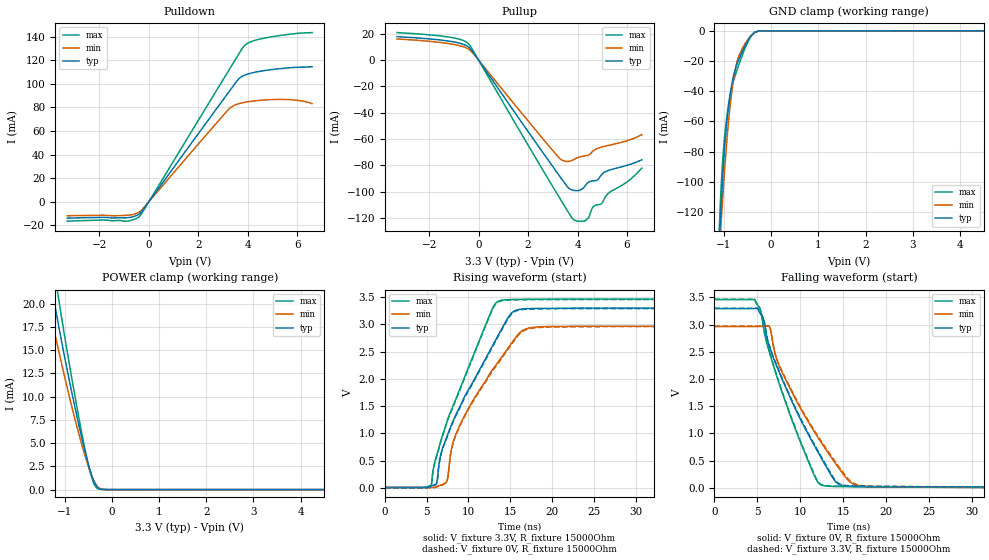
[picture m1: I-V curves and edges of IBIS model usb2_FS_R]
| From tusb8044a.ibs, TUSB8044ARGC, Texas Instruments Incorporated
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|   USB 2.0 Fast Speed mode, for DP pin 6MHz
[Model]   usb2_FS_R
Model_type   I/O
Polarity   Non-Inverting
Enable   Active-High
Vmeas = 1.54
Vref = 0
Rref = 15000
Cref = 50pF
Vinl = 0.8V
Vinh = 2.0V
|   typ   min   max
|   (nom PVT)   (Fast PVT)   (slow PVT)
C_comp   9.0376pF   8.9385pF   9.1512pF
[Voltage Range]   3.3   2.97   3.465
[Temperature Range]   27   105   -40
[Pullup Reference]   3.3   2.97   3.465
[Pulldown Reference]   -0   -0   -0
[Power Clamp Reference]   3.3   2.97   3.465
[GND Clamp Reference]   -0   -0   -0
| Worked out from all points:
|   slope of the pulldown table from 0 to 0.495 V, typ, clamps not added: 34.6 ohm
|   slope of the pullup table from 0 to 0.495 V, typ, clamps not added: 36.8 ohm
|   GND clamp passes 1 mA (typ) near -0.35 V on its own axis
|   POWER clamp passes 1 mA (typ) near -0.39 V on its own axis
|   falling waveform, V_fixture 0V, R_fixture 15000Ohm: 20-80 % time 5.73ns typ, 6.23ns min, 4.47ns max; typ from 3.29 V to 0 V
|   rising waveform, V_fixture 3.3V, R_fixture 15000Ohm: 20-80 % time 6.21ns typ, 6.02ns min, 5.07ns max; typ from 0.008 V to 3.3 V
|   rising waveform, V_fixture 0V, R_fixture 15000Ohm: 20-80 % time 6.24ns typ, 6.08ns min, 5.09ns max; typ from 0 V to 3.29 V
|   falling waveform, V_fixture 3.3V, R_fixture 15000Ohm: 20-80 % time 5.77ns typ, 6.3ns min, 4.5ns max; typ from 3.3 V to 0.008 V
[Pulldown]
|   Voltage   I(typ)   I(min)   I(max)
-3.3V     -13.97mA   -11.94mA   -16.5mA
-1.865V   -13.31mA   -11.55mA   -15.58mA
-948.8mV  -13.78mA   -11.64mA   -16.64mA
-429mV    -11.05mA   -9.328mA   -13.36mA
-255.8mV  -7.37mA    -6.247mA   -8.827mA
3.234V    93.1mA     78.54mA    111.5mA
3.61V     103.6mA    82.92mA    124.4mA
3.858V    107.2mA    84.17mA    132.2mA
4.15V     109.1mA    85.16mA    135.8mA
4.714V    111.3mA    86.32mA    138.9mA
5.798V    113.7mA    86.37mA    142.3mA
6.6V      114.4mA    83.14mA    143.4mA
[GND Clamp]
|   Voltage   I(typ)   I(min)   I(max)
-3.3V     -2.986A    -2.594A    -3.408A
-1.102V   -142.8mA   -148.5mA   -133.6mA
-1.068V   -120.4mA   -130.9mA   -108.6mA
-1.053V   -111.5mA   -123.5mA   -99.43mA
-1.028V   -97.72mA   -111.6mA   -86.34mA
-948.8mV  -63.66mA   -76.9mA    -59.29mA
-874.5mV  -43.76mA   -51.14mA   -43.02mA
-795.3mV  -29.32mA   -31.84mA   -32.77mA
-676.5mV  -18.29mA   -15.93mA   -21.75mA
-458.7mV  -4.679mA   -4.168mA   -5.163mA
-349.8mV  -954.6uA   -1.019mA   -868.7uA
6.6V      27.44uA    21.44uA    34.47uA
[Pullup]
|   Voltage   I(typ)   I(min)   I(max)
-3.3V     17.86mA    16.11mA    20.95mA
-1.162V   14.34mA    12.44mA    17.42mA
-374.6mV  9.504mA    7.922mA    11.72mA
3.224V    -86.72mA   -73.66mA   -103.1mA
3.625V    -96.87mA   -77.02mA   -115.4mA
3.863V    -98.94mA   -75.34mA   -121.4mA
4.303V    -95.54mA   -72.68mA   -122mA
4.452V    -92.62mA   -72.08mA   -119.5mA
4.655V    -91.65mA   -68.64mA   -111mA
4.962V    -87.23mA   -66.09mA   -109.1mA
5.14V     -84.63mA   -65.26mA   -103.4mA
6.6V      -75.66mA   -56.61mA   -82.01mA
[POWER Clamp]
|   Voltage   I(typ)   I(min)   I(max)
-3.3V     96.11mA    80.39mA    114.3mA
-1.409V   25.5mA     21.48mA    30.05mA
-1.315V   22.86mA    19.29mA    26.86mA
-1.246V   20.93mA    17.7mA     24.52mA
-1.127V   17.68mA    15mA       20.59mA
-854.7mV  10.64mA    9.089mA    12.22mA
-567.6mV  4.132mA    3.664mA    4.338mA
-419.1mV  1.439mA    1.425mA    1.205mA
-359.7mV  684.8uA    768.2uA    455.6uA
-290.4mV  187uA      273.4uA    86.97uA
0V        0A         0A         0A
6.6V      0A         0A         0A
[Ramp]
R_load = 15000
|   typ   min   max
dV/dt_r   1.97481/6.20846e-009   1.77621/6.02152e-009   2.07437/5.07374e-009
dV/dt_f   1.97455/5.7255e-009   1.77598/6.2317e-009   2.07413/4.47102e-009
[Falling Waveform]
V_fixture = 0V
V_fixture_min = 0V
V_fixture_max = 0V
R_fixture = 15000Ohm
C_fixture = 0F
|   Time   V(typ)   V(min)   V(max)
0s        3.291V     2.961V     3.457V
4.7ns     3.293V     2.961V     3.458V
5.7ns     3.108V     2.967V     2.957V
6.4ns     2.601V     2.967V     2.494V
7.5ns     2.143V     2.254V     1.936V
11.4ns    846.1mV    1.091V     316.1mV
12.6ns    506.4mV    796.2mV    44.4mV
14.4ns    75.51mV    384.1mV    24.24mV
17.5ns    21.5mV     25.98mV    19.1mV
84.9ns    94.35uV    653.8uV    37.35uV
[Rising Waveform]
|Vcc
V_fixture = 3.3V
V_fixture_min = 2.97V
V_fixture_max = 3.465V
R_fixture = 15000Ohm
C_fixture = 0F
|   Time   V(typ)   V(min)   V(max)
0s        7.658mV    8.716mV    6.679mV
5.5ns     34.03mV    9.217mV    46.24mV
6.2ns     85.76mV    22.01mV    590.8mV
6.6ns     542.7mV    47.18mV    807.5mV
7.4ns     926.5mV    115.1mV    1.193V
8.6ns     1.371V     1.019V     1.668V
13.8ns    2.867V     2.361V     3.438V
15.3ns    3.227V     2.686V     3.457V
18.1ns    3.293V     2.951V     3.462V
84.9ns    3.299V     2.969V     3.464V
[Rising Waveform]
V_fixture = 0V
V_fixture_min = 0V
V_fixture_max = 0V
R_fixture = 15000Ohm
C_fixture = 0F
|   Time   V(typ)   V(min)   V(max)
0s        100.2uV    720.6uV    39.4uV
5.5ns     26.33mV    1.222mV    39.41mV
6.2ns     77.72mV    13.9mV     579.6mV
6.6ns     530.5mV    39.01mV    795.4mV
7.4ns     911.9mV    106.6mV    1.179V
8.6ns     1.353V     1.003V     1.653V
13.8ns    2.848V     2.339V     3.429V
15.5ns    3.233V     2.707V     3.45V
18.3ns    3.285V     2.942V     3.455V
84.9ns    3.291V     2.961V     3.457V
[Falling Waveform]
|Gnd
V_fixture = 3.3V
V_fixture_min = 2.97V
V_fixture_max = 3.465V
R_fixture = 15000Ohm
C_fixture = 0F
|   Time   V(typ)   V(min)   V(max)
0s        3.299V     2.969V     3.464V
4.7ns     3.301V     2.97V      3.465V
5.7ns     3.117V     2.975V     2.966V
6.4ns     2.614V     2.976V     2.506V
7.5ns     2.159V     2.27V      1.952V
11.5ns    841mV      1.091V     299.3mV
12.7ns    502.5mV    798.8mV    49.57mV
14.4ns    91.03mV    411.2mV    31.27mV
17.6ns    29.38mV    35.57mV    25.66mV
84.9ns    7.652mV    8.648mV    6.677mV
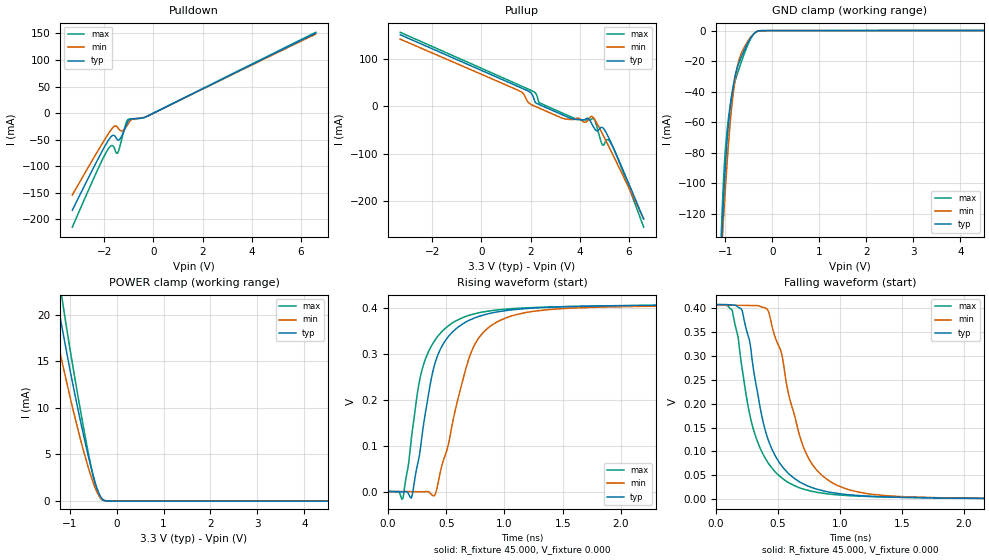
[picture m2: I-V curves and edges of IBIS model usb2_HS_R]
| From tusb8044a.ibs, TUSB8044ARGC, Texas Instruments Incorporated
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|   USB 2.0 High Speed mode, for DP pin 240MHz (Internal Termination ON)
[Model]   usb2_HS_R
Model_type   I/O
Polarity   Non-Inverting
Enable   Active-High
Vmeas = 202mV
Vref = 0
Rref = 45
Cref =1pF
Vinl = 150mV
Vinh = 360mV
|   typ   min   max
|EXCEPTION   (nom PVT)   (Slow PVT) (Fast PVT)
C_comp   6.3538pF   6.1002pF   6.4829pF
|5.8941pF   5.4228pF   6.1646pF
[Voltage Range]   3.3   2.97   3.465
[Temperature Range]   27   105   -40
[Pullup Reference]   3.3   2.97   3.465
[Pulldown Reference]   0   0   0
[Power Clamp Reference]   3.3   2.97   3.465
[GND Clamp Reference]   0   0   0
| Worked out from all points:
|   slope of the pulldown table from 0 to 0.495 V, typ, clamps not added: 43.6 ohm
|   slope of the pullup table from 0 to 0.495 V, typ, clamps not added: 43.7 ohm
|   GND clamp passes 1 mA (typ) near -0.35 V on its own axis
|   POWER clamp passes 1 mA (typ) near -0.39 V on its own axis
|   rising waveform, R_fixture 45.000, V_fixture 0.000: 20-80 % time 214ps typ, 261ps min, 207ps max; typ from 0 V to 0.407 V
|   falling waveform, R_fixture 45.000, V_fixture 0.000: 20-80 % time 225ps typ, 258ps min, 223ps max; typ from 0.407 V to 0 V
[Pulldown]
|   Voltage   I(typ)   I(min)   I(max)
-3.3V     -182.7mA   -154mA     -214.5mA
-2.109V   -73.47mA   -59.12mA   -90.55mA
-1.836V   -51.34mA   -38.81mA   -67.06mA
-1.687V   -42.74mA   -29.04mA   -60.76mA
-1.588V   -42.26mA   -24.56mA   -66.11mA
-1.464V   -49.94mA   -26.46mA   -75.27mA
-1.265V   -40.67mA   -33.14mA   -44.1mA
-1.141V   -26.63mA   -28.06mA   -22.45mA
-1.042V   -16mA      -21.02mA   -12.18mA
-868.4mV  -10.68mA   -11.28mA   -10.85mA
-297.7mV  -6.74mA    -6.624mA   -6.826mA
6.6V      150.7mA    148.8mA    152.1mA
[GND Clamp]
|   Voltage   I(typ)   I(min)   I(max)
-3.3V     -3.521A    -2.996A    -4.111A
-1.092V   -145.9mA   -151.2mA   -136.4mA
-1.067V   -128.4mA   -137.7mA   -116.4mA
-1.042V   -112.2mA   -124.7mA   -99.36mA
-1.017V   -97.56mA   -112.1mA   -85.68mA
-967.7mV  -73.5mA    -88.57mA   -66.63mA
-893.2mV  -49.51mA   -59.02mA   -47.86mA
-818.8mV  -33.69mA   -37.74mA   -35.76mA
-669.9mV  -17.99mA   -15.57mA   -21.42mA
-471.4mV  -5.326mA   -4.698mA   -5.944mA
-322.6mV  -523.8uA   -615.4uA   -432uA
6.6V      27.34uA    21.38uA    34.43uA
[Pullup]
|   Voltage   I(typ)   I(min)   I(max)
-3.3V     150.7mA    141.5mA    155.9mA
1.588V    39.24mA    31.21mA    43.36mA
2.084V    22.84mA    2.078mA    31.83mA
2.357V    3.277mA    -4.287mA   7.257mA
3.25V     -17.25mA   -24.5mA    -13.49mA
4.342V    -25.52mA   -29.54mA   -29.28mA
4.565V    -44.49mA   -24.78mA   -25.96mA
4.714V    -52.12mA   -37.54mA   -46.83mA
4.913V    -44.86mA   -57.23mA   -80.87mA
5.086V    -57mA      -75.14mA   -71.32mA
5.434V    -95.43mA   -111.8mA   -96.58mA
6.6V      -238.4mA   -237.7mA   -255.4mA
[POWER Clamp]
|   Voltage   I(typ)   I(min)   I(max)
-3.3V     96.73mA    79.76mA    115.2mA
-1.439V   26.41mA    21.36mA    31.18mA
-1.265V   21.53mA    17.34mA    25.27mA
-1.241V   20.85mA    16.77mA    24.43mA
-1.141V   18.11mA    14.53mA    21.12mA
-843.6mV  10.39mA    8.125mA    11.91mA
-570.7mV  4.197mA    3.107mA    4.415mA
-421.8mV  1.476mA    1.033mA    1.243mA
-372.2mV  816.7uA    565.7uA    573.1uA
-297.7mV  217.2uA    160.3uA    102.4uA
0V        0A         0A         0A
6.6V      0A         0A         0A
[Ramp]
R_load = 45
|   typ   min   max
dV/dt_r   0.241436/2.13719e-10   0.240166/2.60796e-10   0.241677/2.07061e-10
dV/dt_f   0.241444/2.2514e-10   0.240152/2.57832e-10   0.241591/2.23371e-10
[Rising Waveform]
R_fixture = 45.000
V_fixture = 0.000
V_fixture_min = 0.000
V_fixture_max = 0.000
|  time   V(typ)   V(min)   V(max)
0s        11.24uV    5.401uV    22.98uV
130ps     -771.8uV   -133.3uV   -13.14mV
200ps     -14.17mV   -290.1uV   114.9mV
280ps     98.17mV    -662uV     252.8mV
400ps     276.5mV    -8.747mV   328.3mV
600ps     357.5mV    201.2mV    373.6mV
700ps     372.9mV    293.4mV    383.8mV
780ps     381.2mV    334.5mV    389mV
1.08ns    395.8mV    383.6mV    398.2mV
3.4ns     407mV      405.3mV    406.8mV
[Falling Waveform]
R_fixture = 45.000
V_fixture = 0.000
V_fixture_min = 0.000
V_fixture_max = 0.000
|  time   V(typ)   V(min)   V(max)
0s        407mV      405.3mV    406.8mV
130ps     406mV      405.4mV    395.7mV
210ps     395.4mV    405.3mV    274.2mV
300ps     275.3mV    404.8mV    148mV
420ps     125.3mV    394.3mV    76.43mV
530ps     70.04mV    303.9mV    44.94mV
640ps     42.29mV    169.1mV    27.77mV
790ps     23.09mV    68.43mV    15.83mV
1.08ns    9.333mV    19.46mV    7.581mV
3.4ns     11.24uV    5.401uV    22.98uV
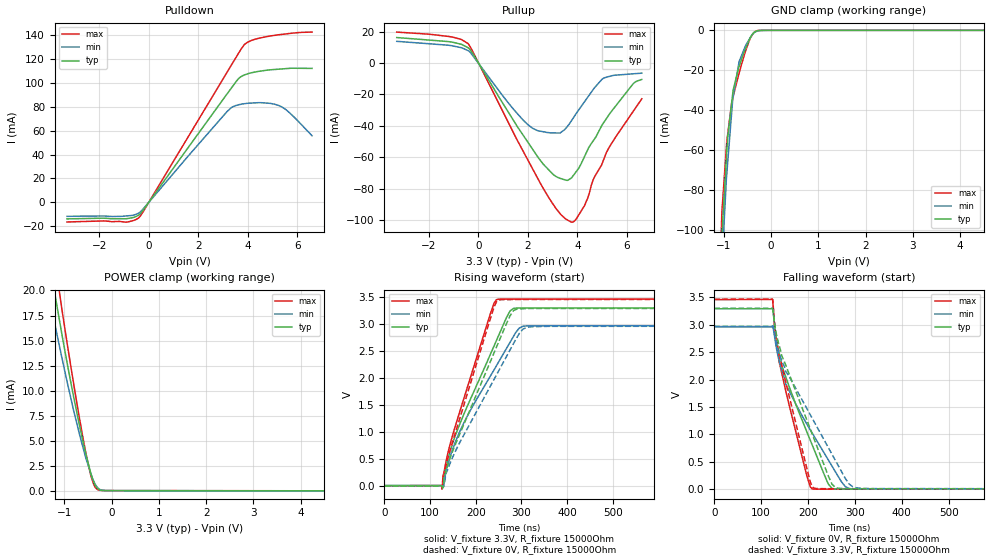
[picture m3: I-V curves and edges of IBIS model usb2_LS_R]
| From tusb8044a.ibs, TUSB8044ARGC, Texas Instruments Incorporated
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|   USB 2.0 Low Speed mode, for DP/DM pin with Rfixture only 750KHz
[Model]   usb2_LS_R
Model_type   I/O
Polarity   Non-Inverting
Enable   Active-High
Vmeas = 1.32V
Vref = 0
Rref = 15000
Cref = 600pF
Vinl = 0.8V
Vinh = 2.0V
|   typ   min   max
|   (nom PVT)   (Fast PVT)   (slow PVT)
C_comp   9.3159pF   9.1524pF   9.4841pF
[Voltage Range]   3.3   2.97   3.465
[Temperature Range]   27   105   -40
[Pullup Reference]   3.3   2.97   3.465
[Pulldown Reference]   0   0   0
[Power Clamp Reference]   3.3   2.97   3.465
[GND Clamp Reference]   0   0   0
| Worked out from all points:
|   slope of the pulldown table from 0 to 0.495 V, typ, clamps not added: 34.7 ohm
|   slope of the pullup table from 0 to 0.495 V, typ, clamps not added: 38.2 ohm
|   GND clamp passes 1 mA (typ) near -0.35 V on its own axis
|   POWER clamp passes 1 mA (typ) near -0.38 V on its own axis
|   falling waveform, V_fixture 0V, R_fixture 15000Ohm: 20-80 % time 81.1ns typ, 101ns min, 53.1ns max; typ from 3.29 V to 0 V
|   rising waveform, V_fixture 3.3V, R_fixture 15000Ohm: 20-80 % time 97.7ns typ, 109ns min, 75.1ns max; typ from 0.008 V to 3.3 V
|   rising waveform, V_fixture 0V, R_fixture 15000Ohm: 20-80 % time 98.3ns typ, 113ns min, 74.9ns max; typ from 0 V to 3.29 V
|   falling waveform, V_fixture 3.3V, R_fixture 15000Ohm: 20-80 % time 86.3ns typ, 111ns min, 56.1ns max; typ from 3.3 V to 0.008 V
[Pulldown]
|   Voltage   I(typ)   I(min)   I(max)
-3.3V     -13.8mA    -11.67mA   -16.38mA
-1.818V   -13.22mA   -11.38mA   -15.5mA
-933.8mV  -13.69mA   -11.39mA   -16.56mA
-393.4mV  -10.5mA    -8.814mA   -12.71mA
3.144V    90.09mA    75.48mA    108.1mA
3.518V    100.7mA    80.99mA    120.9mA
3.716V    105mA      82.04mA    127.7mA
3.979V    107.4mA    82.87mA    133.8mA
4.553V    109.9mA    83.38mA    137.7mA
5.239V    111.4mA    81.15mA    140.2mA
5.684V    112.1mA    75.09mA    141.3mA
6.6V      112.1mA    55.7mA     142.4mA
[GND Clamp]
|   Voltage   I(typ)   I(min)   I(max)
-3.3V     -2.986A    -2.594A    -3.408A
-1.078V   -130.7mA   -136.1mA   -123.1mA
-1.035V   -101.8mA   -116.7mA   -90.38mA
-933.8mV  -60.8mA    -71.89mA   -55.6mA
-917.7mV  -54.32mA   -67.11mA   -52.63mA
-830mV    -36.19mA   -40.99mA   -36.44mA
-800mV    -30mA      -33.29mA   -33.41mA
-672.6mV  -18.05mA   -15.62mA   -21.44mA
-537.4mV  -9.128mA   -7.685mA   -10.37mA
-452.6mV  -4.449mA   -4.267mA   -4.821mA
-311.3mV  -500.4uA   -565.3uA   -312.4uA
6.6V      0A         0A         0A
[Pullup]
|   Voltage   I(typ)   I(min)   I(max)
-3.3V     16.19mA    13.77mA    19.64mA
-422.2mV  9.743mA    7.891mA    12.39mA
1.406V    -36.22mA   -29.18mA   -44.02mA
2.198V    -55mA      -41.55mA   -67.51mA
3.296V    -73.26mA   -44.5mA    -95.68mA
3.744V    -73.22mA   -37.02mA   -101mA
4.291V    -59.28mA   -24.5mA    -90.47mA
4.637V    -49.45mA   -16.86mA   -74.15mA
4.997V    -39.36mA   -10.25mA   -63.91mA
5.347V    -31.31mA   -8.288mA   -51.9mA
6.247V    -13.27mA   -6.876mA   -30.86mA
6.6V      -10.45mA   -6.447mA   -22.73mA
[POWER Clamp]
|   Voltage   I(typ)   I(min)   I(max)
-3.3V     96.14mA    80.42mA    114.3mA
-1.357V   24.07mA    20.31mA    28.32mA
-1.197V   19.63mA    16.62mA    22.94mA
-1.078V   16.4mA     13.92mA    19.06mA
-917.7mV  12.22mA    10.44mA    14.11mA
-762.7mV  8.497mA    7.289mA    9.602mA
-540.3mV  3.645mA    3.234mA    3.714mA
-422.2mV  1.516mA    1.529mA    1.289mA
-358.7mV  704.2uA    786.5uA    480.4uA
-291.5mV  239.5uA    302.9uA    123.9uA
-75.48mV  29.65uA    23.12uA    37.69uA
6.6V      0A         0A         0A
[Ramp]
R_load = 15000
|   typ   min   max
dV/dt_r   1.97483/9.77725e-008   1.77658/1.09368e-007   2.07436/7.50271e-008
dV/dt_f   1.97441/8.12338e-008   1.77599/1.01626e-007   2.07403/5.31391e-008
[Falling Waveform]
V_fixture = 0V
V_fixture_min = 0V
V_fixture_max = 0V
R_fixture = 15000Ohm
C_fixture = 0F
|   Time   V(typ)   V(min)   V(max)
0s        3.291V     2.96V      3.457V
124ns     3.293V     2.964V     3.46V
130.3ns   2.875V     2.696V     2.835V
138.5ns   2.484V     2.343V     2.318V
153.7ns   2.019V     1.895V     1.75V
197.6ns   1.044V     1.186V     240mV
209.3ns   798.1mV    1.018V     3.984mV
251.1ns   13.55mV    420.9mV    73.85uV
287.3ns   -137.7uV   10.64mV    68.96uV
763.1ns   3.774uV    9.494uV    4.745uV
[Rising Waveform]
|Vcc
V_fixture = 3.3V
V_fixture_min = 2.97V
V_fixture_max = 3.465V
R_fixture = 15000Ohm
C_fixture = 0F
|   Time   V(typ)   V(min)   V(max)
0s        7.583mV    8.051mV    6.654mV
126.1ns   9.097mV    7.622mV    -43.05mV
128.3ns   23.29mV    9.478mV    187.2mV
130.8ns   222.3mV    64.18mV    272mV
148.5ns   770.9mV    660.2mV    918.6mV
180.8ns   1.465V     1.285V     1.807V
245.3ns   2.697V     2.229V     3.452V
275.1ns   3.244V     2.663V     3.464V
303.3ns   3.298V     2.96V      3.464V
763.1ns   3.299V     2.969V     3.464V
[Rising Waveform]
V_fixture = 0V
V_fixture_min = 0V
V_fixture_max = 0V
R_fixture = 15000Ohm
C_fixture = 0F
|   Time   V(typ)   V(min)   V(max)
0s        3.743uV    9.417uV    4.73uV
126.1ns   997uV      -506.7uV   -58.29mV
128.3ns   1.896mV    1.083mV    156.3mV
130.8ns   181.6mV    35.32mV    226.1mV
145.2ns   551mV      450.7mV    703.4mV
240.3ns   2.471V     1.979V     3.318V
250.4ns   2.674V     2.136V     3.446V
283.1ns   3.253V     2.645V     3.455V
311.3ns   3.288V     2.939V     3.457V
763.1ns   3.291V     2.96V      3.457V
[Falling Waveform]
|Gnd
V_fixture = 3.3V
V_fixture_min = 2.97V
V_fixture_max = 3.465V
R_fixture = 15000Ohm
C_fixture = 0F
|   Time   V(typ)   V(min)   V(max)
0s        3.299V     2.969V     3.464V
124ns     3.302V     2.973V     3.467V
130.1ns   2.954V     2.769V     2.912V
138.3ns   2.629V     2.483V     2.45V
204.9ns   1.094V     1.355V     128.6mV
213.6ns   900.6mV    1.22V      15.45mV
251.1ns   90.61mV    637.4mV    6.908mV
287.3ns   10.64mV    96.44mV    6.89mV
303.3ns   8.401mV    24.24mV    6.882mV
763.1ns   7.583mV    8.051mV    6.654mV
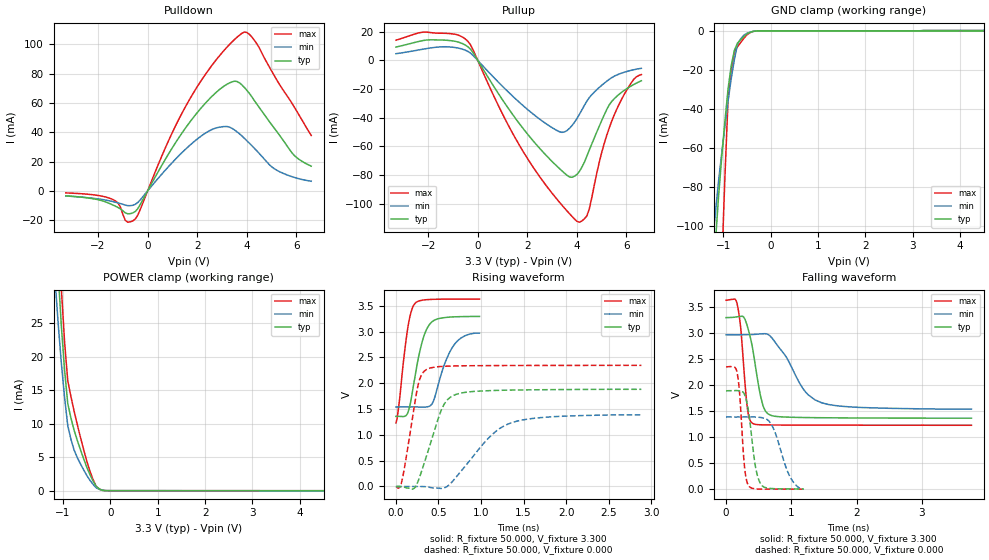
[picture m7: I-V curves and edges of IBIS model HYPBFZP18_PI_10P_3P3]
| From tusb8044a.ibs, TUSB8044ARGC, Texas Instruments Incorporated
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|   Model Cell HYPBFZP18_PI_10P_3P3
|BC3340DSHYPBFZP18_PI_10P_3P3
[Model]   HYPBFZP18_PI_10P_3P3
Model_type   I/O
Polarity   Non-Inverting
Enable   Active-Low
Vinl =  0.8V
Vinh =  2V
Cref =  7pF
Rref =  100.00M
Vref =  0V
Vmeas =  1.65
C_comp   1.726631p   1.582948p   1.812054p
[Model Spec]
Vinl   0.8V   0.8V   0.8V
Vinh   2V   2V   2V
[Temperature Range]   25   125   -40
[Voltage Range]   3.3   2.97   3.63
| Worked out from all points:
|   slope of the pulldown table from 0 to 0.495 V, typ, clamps not added: 32.6 ohm
|   slope of the pullup table from 0 to 0.495 V, typ, clamps not added: 35.4 ohm
|   GND clamp passes 1 mA (typ) near -0.45 V on its own axis
|   POWER clamp passes 1 mA (typ) near -0.33 V on its own axis
|   rising waveform, R_fixture 50.000, V_fixture 3.300: 20-80 % time 143ps typ, 187ps min, 103ps max; typ from 1.36 V to 3.29 V
|   rising waveform, R_fixture 50.000, V_fixture 0.000: 20-80 % time 223ps typ, 452ps min, 139ps max; typ from 0 V to 1.88 V
|   falling waveform, R_fixture 50.000, V_fixture 3.300: 20-80 % time 163ps typ, 413ps min, 93.5ps max; typ from 3.3 V to 1.36 V
|   falling waveform, R_fixture 50.000, V_fixture 0.000: 20-80 % time 117ps typ, 220ps min, 74.4ps max; typ from 1.89 V to 0.003 V
[POWER_clamp]
|   voltage   I(typ)   I(min)   I(max)
-3.3V     369.6mA    284.8mA    471.8mA
-1.167V   41.03mA    31.43mA    51.19mA
-1.1V     32.16mA    24.74mA    39.89mA
-1.033V   24.41mA    18.89mA    30.01mA
-966.7mV  18.03mA    13.89mA    22.19mA
-900mV    13.01mA    9.733mA    16.43mA
-766.7mV  9.049mA    6.093mA    11.9mA
-500mV    3.542mA    2.3mA      4.461mA
-300mV    640.4uA    437uA      619.2uA
-233.3mV  273.6uA    198.6uA    246.8uA
-33.33mV  5.413uA    4.415uA    8.868uA
6.6V      -215.7nA   -34.8uA    -30.76nA
[Pulldown]
|   voltage   I(typ)   I(min)   I(max)
-3.3V     -3.365mA   -3.408mA   -1.35mA
-1.5V     -8.823mA   -6.868mA   -5.16mA
-1.2V     -11.25mA   -8.144mA   -8.194mA
-900mV    -14.96mA   -9.653mA   -20.06mA
-500mV    -14.05mA   -9.144mA   -19.19mA
1.1V      32.18mA    21.23mA    43.46mA
2.4V      61.1mA     40.13mA    81.13mA
3.4V      74.34mA    42.73mA    101.5mA
3.9V      70.64mA    35.96mA    108.3mA
5.1V      43.02mA    15.26mA    78.93mA
5.9V      24.48mA    9.306mA    57.71mA
6.6V      16.92mA    6.609mA    37.85mA
[Pullup]
|   voltage   I(typ)   I(min)   I(max)
-3.3V     9.309mA    4.668mA    14.12mA
-2.1V     14.15mA    8.14mA     19.77mA
-400mV    9.543mA    6.3mA      13.38mA
1.5V      -39.97mA   -26.45mA   -53.78mA
3.1V      -72.31mA   -48.02mA   -94.94mA
3.6V      -80.23mA   -49.04mA   -105.1mA
4.1V      -77.58mA   -37.73mA   -113mA
4.5V      -62.66mA   -25.98mA   -103.7mA
5V        -42.07mA   -17.41mA   -64.41mA
5.5V      -26.88mA   -11.08mA   -38.35mA
6.2V      -17.74mA   -6.877mA   -15.47mA
6.6V      -14.22mA   -5.549mA   -9.882mA
[GND_clamp]
|   voltage   I(typ)   I(min)   I(max)
-3.3V     -996.3mA   -831.9mA   -2.048A
-1.233V   -134.2mA   -111.3mA   -283.3mA
-1.167V   -109.2mA   -93.69mA   -227.4mA
-1.1V     -85.3mA    -77.39mA   -172.3mA
-1.033V   -65.22mA   -63.13mA   -121.7mA
-966.7mV  -46.84mA   -49.44mA   -76.28mA
-900mV    -30.14mA   -36.33mA   -36.16mA
-833.3mV  -18.07mA   -24.79mA   -20.33mA
-766.7mV  -10.12mA   -14.98mA   -11.03mA
-700mV    -6.271mA   -6.911mA   -8.236mA
-500mV    -1.565mA   -1.211mA   -1.981mA
6.6V      3.807uA    305.7uA    8.152uA
[Ramp]
| variable   typ   min   max
dV/dt_f   1.18035/0.1660952n  0.8590365/0.4364875n   1.457049/94.57634p
dV/dt_r   1.167005/0.2296879n  0.8504954/0.4873644n   1.449474/0.1402688n
R_load = 50
[Rising Waveform]
R_fixture = 50.000
V_fixture = 3.300
V_fixture_min = 2.970
V_fixture_max = 3.630
|  time   V(typ)   V(min)   V(max)
0s        1.358V     1.54V      1.232V
34.5ps    1.358V     1.54V      1.572V
133.5ps   1.407V     1.54V      3.009V
211.5ps   2.006V     1.54V      3.518V
310.5ps   2.814V     1.538V     3.608V
405ps     3.16V      1.566V     3.623V
457.5ps   3.225V     1.733V     3.626V
577.5ps   3.272V     2.397V     3.628V
676.5ps   3.285V     2.726V     3.629V
982.5ps   3.294V     2.97V      3.63V
[Rising Waveform]
R_fixture = 50.000
V_fixture = 0.000
V_fixture_min = 0.000
V_fixture_max = 0.000
|  time   V(typ)   V(min)   V(max)
0s        220.7uV    24.97uV    807.4nV
70.5ps    -3.233mV   13.36uV    109.1mV
223.5ps   -19.04mV   63.09uV    1.63V
288ps     227.8mV    -91.93uV   2.116V
373.5ps   662.9mV    -9.041mV   2.277V
567ps     1.595V     -28.26mV   2.328V
738ps     1.799V     241.9mV    2.336V
1.115ns   1.857V     980.2mV    2.341V
1.356ns   1.867V     1.234V     2.343V
2.885ns   1.882V     1.388V     2.346V
[Falling Waveform]
R_fixture = 50.000
V_fixture = 3.300
V_fixture_min = 2.970
V_fixture_max = 3.630
|  time   V(typ)   V(min)   V(max)
0s        3.299V     2.97V      3.633V
166.5ps   3.314V     2.969V     3.58V
228ps     3.324V     2.97V      3.06V
331.5ps   3.111V     2.972V     1.517V
418.5ps   2.622V     2.975V     1.259V
565.5ps   1.607V     2.989V     1.237V
711ps     1.411V     2.897V     1.234V
1.184ns   1.378V     1.926V     1.232V
1.464ns   1.374V     1.662V     1.231V
3.762ns   1.365V     1.54V      1.229V
[Falling Waveform]
R_fixture = 50.000
V_fixture = 0.000
V_fixture_min = 0.000
V_fixture_max = 0.000
|  time   V(typ)   V(min)   V(max)
0s        1.892V     1.388V     2.352V
172.5ps   1.896V     1.388V     2.221V
207ps     1.891V     1.388V     1.86V
285ps     1.816V     1.389V     403.5mV
346.5ps   1.481V     1.389V     62.56mV
453ps     418.2mV    1.387V     5.693mV
529.5ps   103mV      1.379V     1.245mV
684ps     13.61mV    1.267V     158.8uV
976.5ps   4.484mV    248.6mV    87.2uV
1.19ns    3.344mV    24.97uV    67.59uV
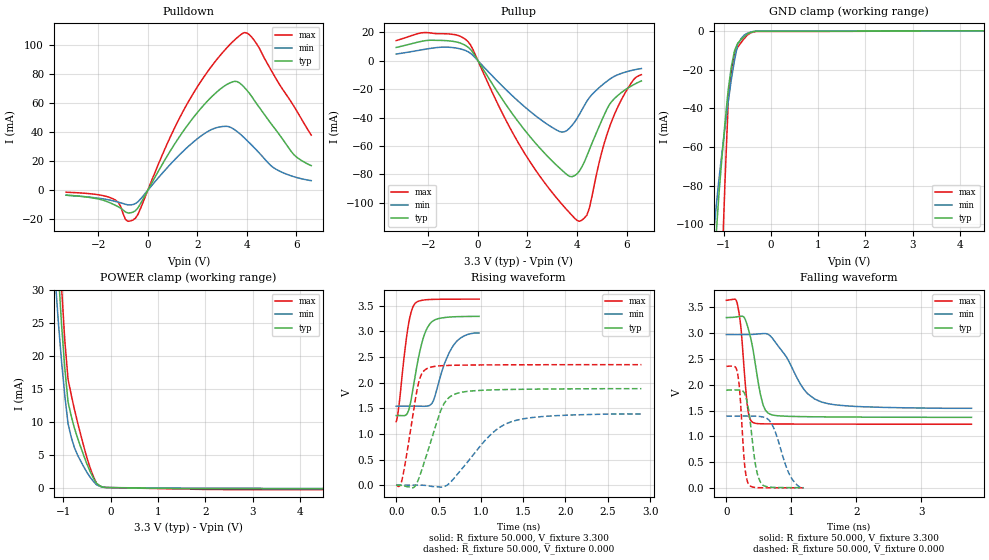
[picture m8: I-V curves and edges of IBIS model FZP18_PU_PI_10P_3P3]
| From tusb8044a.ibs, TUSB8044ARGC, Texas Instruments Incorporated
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|   Model Cell FZP18_PU_PI_10P_3P3
|BC3340DSHYPBFZP18_PU_PI_10P_3P3
[Model]   FZP18_PU_PI_10P_3P3
Model_type   I/O
Polarity   Non-Inverting
Enable   Active-Low
Vinl =  0.8V
Vinh =  2V
Cref =  7pF
Rref =  100.00M
Vref =  0V
Vmeas =  1.65
C_comp   1.726631p   1.582948p   1.812054p
[Model Spec]
Vinl   0.8V   0.8V   0.8V
Vinh   2V   2V   2V
[Temperature Range]   25   125   -40
[Voltage Range]   3.3   2.97   3.63
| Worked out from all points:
|   slope of the pulldown table from 0 to 0.495 V, typ, clamps not added: 32.6 ohm
|   slope of the pullup table from 0 to 0.495 V, typ, clamps not added: 35.4 ohm
|   GND clamp passes 1 mA (typ) near -0.44 V on its own axis
|   POWER clamp passes 1 mA (typ) near -0.33 V on its own axis
|   rising waveform, R_fixture 50.000, V_fixture 3.300: 20-80 % time 142ps typ, 186ps min, 103ps max; typ from 1.36 V to 3.29 V
|   rising waveform, R_fixture 50.000, V_fixture 0.000: 20-80 % time 223ps typ, 452ps min, 138ps max; typ from 0.004 V to 1.89 V
|   falling waveform, R_fixture 50.000, V_fixture 3.300: 20-80 % time 163ps typ, 413ps min, 93.5ps max; typ from 3.3 V to 1.37 V
|   falling waveform, R_fixture 50.000, V_fixture 0.000: 20-80 % time 117ps typ, 220ps min, 74.4ps max; typ from 1.9 V to 0.007 V
[POWER_clamp]
|   voltage   I(typ)   I(min)   I(max)
-3.3V     369.6mA    284.8mA    471.9mA
-1.167V   41.09mA    31.46mA    51.28mA
-1.1V     32.22mA    24.77mA    39.98mA
-1.033V   24.47mA    18.92mA    30.09mA
-966.7mV  18.08mA    13.92mA    22.27mA
-900mV    13.06mA    9.763mA    16.52mA
-766.7mV  9.1mA      6.122mA    11.98mA
-500mV    3.584mA    2.324mA    4.526mA
-300mV    669.8uA    453.6uA    665.1uA
-233.3mV  297.2uA    211.9uA    283.3uA
1.967V    -169.8uA   -90.3uA    -272.6uA
6.6V      -184.2uA   -116.5uA   -312.8uA
[Pulldown]
|   voltage   I(typ)   I(min)   I(max)
-3.3V     -3.365mA   -3.408mA   -1.35mA
-1.5V     -8.823mA   -6.868mA   -5.16mA
-1.2V     -11.25mA   -8.144mA   -8.195mA
-900mV    -14.96mA   -9.653mA   -20.07mA
-500mV    -14.05mA   -9.144mA   -19.19mA
1.1V      32.18mA    21.23mA    43.46mA
2.4V      61.1mA     40.13mA    81.13mA
3.4V      74.34mA    42.73mA    101.5mA
3.9V      70.64mA    35.96mA    108.3mA
5.1V      43.02mA    15.26mA    78.93mA
5.9V      24.48mA    9.306mA    57.71mA
6.6V      16.92mA    6.609mA    37.85mA
[Pullup]
|   voltage   I(typ)   I(min)   I(max)
-3.3V     9.309mA    4.668mA    14.12mA
-2.1V     14.15mA    8.14mA     19.77mA
-400mV    9.542mA    6.3mA      13.38mA
1.5V      -39.97mA   -26.45mA   -53.78mA
3.2V      -73.97mA   -49mA      -97.05mA
3.7V      -81.4mA    -47.46mA   -107mA
4.1V      -77.58mA   -37.73mA   -113mA
4.5V      -62.66mA   -25.98mA   -103.7mA
5V        -42.07mA   -17.41mA   -64.41mA
5.5V      -26.88mA   -11.08mA   -38.35mA
6.2V      -17.74mA   -6.877mA   -15.47mA
6.6V      -14.22mA   -5.549mA   -9.882mA
[GND_clamp]
|   voltage   I(typ)   I(min)   I(max)
-3.3V     -996.3mA   -831.9mA   -2.048A
-1.233V   -134.2mA   -111.3mA   -283.3mA
-1.167V   -109.2mA   -93.7mA    -227.5mA
-1.1V     -85.34mA   -77.41mA   -172.4mA
-1.033V   -65.28mA   -63.15mA   -121.7mA
-966.7mV  -46.91mA   -49.47mA   -76.39mA
-900mV    -30.23mA   -36.37mA   -36.32mA
-833.3mV  -18.18mA   -24.83mA   -20.53mA
-766.7mV  -10.24mA   -15.03mA   -11.25mA
-700mV    -6.403mA   -6.967mA   -8.474mA
-500mV    -1.721mA   -1.282mA   -2.254mA
6.6V      0A         0A         0A
[Ramp]
| variable   typ   min   max
dV/dt_f   1.178019/0.1660576n  0.8577423/0.4365275n   1.453588/94.5375p
dV/dt_r   1.16633/0.2292103n  0.8502158/0.4862978n   1.448067/0.1399383n
R_load = 50
[Rising Waveform]
R_fixture = 50.000
V_fixture = 3.300
V_fixture_min = 2.970
V_fixture_max = 3.630
|  time   V(typ)   V(min)   V(max)
0s        1.362V     1.544V     1.243V
34.5ps    1.361V     1.544V     1.584V
133.5ps   1.411V     1.544V     3.019V
211.5ps   2.011V     1.544V     3.521V
310.5ps   2.819V     1.542V     3.609V
405ps     3.162V     1.57V      3.623V
456ps     3.225V     1.729V     3.626V
576ps     3.272V     2.395V     3.628V
675ps     3.285V     2.725V     3.629V
979.5ps   3.294V     2.97V      3.63V
[Rising Waveform]
R_fixture = 50.000
V_fixture = 0.000
V_fixture_min = 0.000
V_fixture_max = 0.000
|  time   V(typ)   V(min)   V(max)
0s        3.59mV     4.28mV     9.733mV
70.5ps    134.1uV    4.269mV    121.4mV
214.5ps   -29.56mV   4.306mV    1.551V
273ps     161.6mV    4.301mV    2.055V
358.5ps   591.2mV    -1.511mV   2.273V
565.5ps   1.596V     -24.23mV   2.335V
702ps     1.785V     175.6mV    2.342V
1.113ns   1.86V      983.9mV    2.348V
1.355ns   1.87V      1.239V     2.35V
2.897ns   1.885V     1.392V     2.353V
[Falling Waveform]
R_fixture = 50.000
V_fixture = 3.300
V_fixture_min = 2.970
V_fixture_max = 3.630
|  time   V(typ)   V(min)   V(max)
0s        3.299V     2.97V      3.633V
166.5ps   3.314V     2.969V     3.58V
228ps     3.324V     2.97V      3.061V
331.5ps   3.111V     2.972V     1.521V
418.5ps   2.622V     2.975V     1.264V
565.5ps   1.61V      2.989V     1.243V
711ps     1.414V     2.897V     1.241V
1.22ns    1.382V     1.87V      1.238V
1.466ns   1.378V     1.665V     1.237V
3.776ns   1.369V     1.544V     1.235V
[Falling Waveform]
R_fixture = 50.000
V_fixture = 0.000
V_fixture_min = 0.000
V_fixture_max = 0.000
|  time   V(typ)   V(min)   V(max)
0s        1.895V     1.392V     2.356V
172.5ps   1.899V     1.392V     2.225V
207ps     1.894V     1.393V     1.865V
285ps     1.819V     1.394V     408.7mV
346.5ps   1.485V     1.393V     66.62mV
453ps     422.5mV    1.392V     10.7mV
529.5ps   106.4mV    1.383V     6.697mV
684ps     17.09mV    1.272V     5.906mV
976.5ps   8.486mV    253.6mV    5.741mV
1.19ns    7.386mV    4.28mV     5.677mV
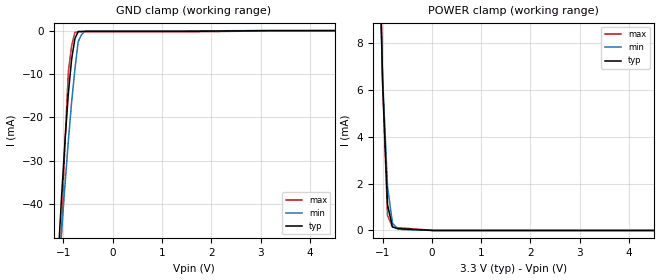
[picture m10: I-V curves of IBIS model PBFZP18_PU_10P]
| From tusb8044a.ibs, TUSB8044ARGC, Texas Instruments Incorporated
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|   Model Cell PBFZP18_PU_10P
|IC33SHYPBFZP18_PU_3P3
[Model]   PBFZP18_PU_10P
Model_type   Input
Polarity   Non-Inverting
Vinl =  0.8V
Vinh =  2V
C_comp   0.3896289p   0.315767p   0.4571448p
[Model Spec]
Vinl   0.8V   0.8V   0.8V
Vinh   2V   2V   2V
[Temperature Range]   25   125   -40
[Voltage Range]   3.3   2.97   3.63
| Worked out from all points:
|   GND clamp passes 1 mA (typ) near -0.73 V on its own axis
|   POWER clamp passes 1 mA (typ) near -0.89 V on its own axis
[POWER_clamp]
|   voltage   I(typ)   I(min)   I(max)
-3.3V     301.3mA    233.2mA    387.8mA
-1.033V   9.499mA    8.962mA    10.24mA
-1V       6.393mA    6.576mA    6.311mA
-900mV    1.111mA    1.887mA    646.5uA
-800mV    151.7uA    319.3uA    149uA
-700mV    81.41uA    74.53uA    121.4uA
0V        0A         0A         0A
6.6V      0A         0A         0A
[GND_clamp]
|   voltage   I(typ)   I(min)   I(max)
-3.3V     -758.5mA   -699.4mA   -1.009A
-1.1V     -51.2mA    -56.68mA   -67.12mA
-1.033V   -37.59mA   -45.83mA   -44.9mA
-966.7mV  -25.38mA   -35.44mA   -25.71mA
-900mV    -14.56mA   -25.49mA   -9.56mA
-833.3mV  -6.657mA   -16.56mA   -3.522mA
-766.7mV  -1.875mA   -8.917mA   -435.3uA
-700mV    -213.4uA   -2.571mA   -301uA
-633.3mV  -187.2uA   -983uA     -300uA
-566.7mV  -174uA     -154.6uA   -299.5uA
6.6V      0A         0A         0A
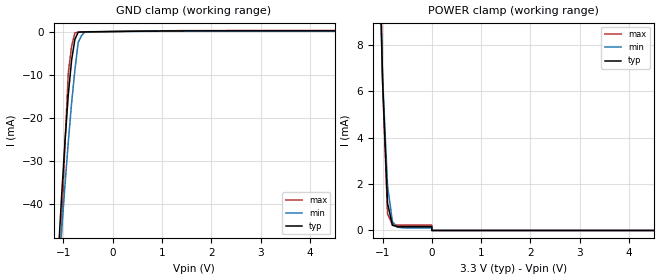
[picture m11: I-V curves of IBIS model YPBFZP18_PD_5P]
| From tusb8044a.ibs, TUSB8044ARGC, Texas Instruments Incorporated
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|   Model Cell YPBFZP18_PD_5P
|IC33SHYPBFZP18_PD_3P3
[Model]   YPBFZP18_PD_5P
Model_type   Input
Polarity   Non-Inverting
Vinl =  0.8V
Vinh =  2V
C_comp   0.3896289p   0.3157674p   0.4571453p
[Model Spec]
Vinl   0.8V   0.8V   0.8V
Vinh   2V   2V   2V
[Temperature Range]   25   125   -40
[Voltage Range]   3.3   3.135   3.465
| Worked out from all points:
|   GND clamp passes 1 mA (typ) near -0.73 V on its own axis
|   POWER clamp passes 1 mA (typ) near -0.88 V on its own axis
[POWER_clamp]
|   voltage   I(typ)   I(min)   I(max)
-3.3V     301.3mA    233.2mA    387.9mA
-1.033V   9.548mA    9.007mA    10.3mA
-1V       6.445mA    6.624mA    6.376mA
-900mV    1.172mA    1.941mA    723.3uA
-800mV    224.1uA    379.6uA    240.7uA
-700mV    164.7uA    141.1uA    229.1uA
-11.55fV  161.3uA    111.1uA    228.1uA
0V        0A         0A         0A
6.6V      0A         0A         0A
[GND_clamp]
|   voltage   I(typ)   I(min)   I(max)
-3.3V     -758.5mA   -699.4mA   -1.009A
-1.1V     -51.19mA   -56.68mA   -67.09mA
-1.033V   -37.57mA   -45.84mA   -44.85mA
-966.7mV  -25.35mA   -35.44mA   -25.65mA
-900mV    -14.52mA   -25.49mA   -9.463mA
-833.3mV  -6.608mA   -16.55mA   -3.405mA
-766.7mV  -1.815mA   -8.902mA   -301.2uA
-700mV    -143.5uA   -2.55mA    -153.2uA
-633.3mV  -107.8uA   -955.8uA   -138.4uA
-566.7mV  -84.85uA   -121.5uA   -124uA
1.367V    143.6uA    93.13uA    204.4uA
6.6V      161.2uA    111.1uA    227.9uA
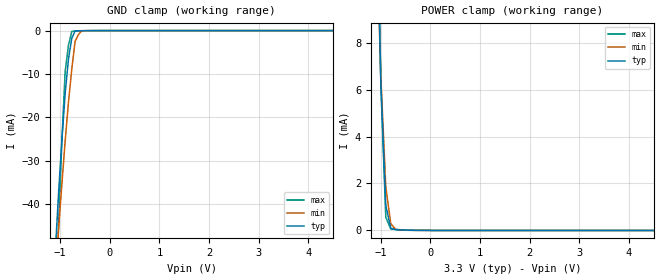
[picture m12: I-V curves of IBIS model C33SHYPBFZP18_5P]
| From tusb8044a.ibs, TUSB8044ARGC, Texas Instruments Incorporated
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|   Model Cell C33SHYPBFZP18_5P
|IC33SHYPBFZP18_3P3
[Model]   C33SHYPBFZP18_5P
Model_type   Input
Polarity   Non-Inverting
Vinl =  0.8V
Vinh =  2V
C_comp   0.3896289p   0.3157674p   0.4571453p
[Model Spec]
Vinl   0.8V   0.8V   0.8V
Vinh   2V   2V   2V
[Temperature Range]   25   125   -40
[Voltage Range]   3.3   3.135   3.465
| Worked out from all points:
|   GND clamp passes 1 mA (typ) near -0.74 V on its own axis
|   POWER clamp passes 1 mA (typ) near -0.89 V on its own axis
[POWER_clamp]
|   voltage   I(typ)   I(min)   I(max)
-3.3V     301.3mA    233.2mA    387.8mA
-1.033V   9.442mA    8.932mA    10.15mA
-1V       6.337mA    6.546mA    6.224mA
-900mV    1.056mA    1.857mA    561uA
-800mV    99.62uA    290.6uA    66.56uA
-700mV    32.23uA    47.35uA    43.27uA
-500mV    15.38uA    9.635uA    22.45uA
6.6V      0A         0A         0A
[GND_clamp]
|   voltage   I(typ)   I(min)   I(max)
-3.3V     -758.5mA   -699.4mA   -1.009A
-1.1V     -51.16mA   -56.67mA   -67.06mA
-1.033V   -37.54mA   -45.82mA   -44.82mA
-966.7mV  -25.31mA   -35.42mA   -25.6mA
-900mV    -14.48mA   -25.46mA   -9.398mA
-833.3mV  -6.552mA   -16.52mA   -3.322mA
-766.7mV  -1.754mA   -8.869mA   -210.3uA
-700mV    -81.77uA   -2.516mA   -62.52uA
-633.3mV  -47.18uA   -921.9uA   -49.43uA
-566.7mV  -25.83uA   -88.29uA   -37.17uA
6.6V      3.911uA    2.564uA    6.936uA
